VERSION 5.7 ;
  NOWIREEXTENSIONATPIN ON ;
  DIVIDERCHAR "/" ;
  BUSBITCHARS "[]" ;
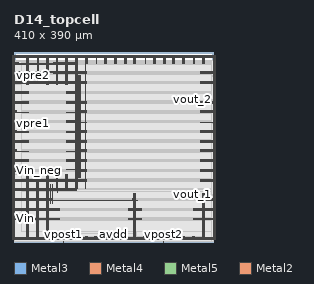
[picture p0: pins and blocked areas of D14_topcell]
MACRO D14_topcell
  CLASS BLOCK ;
  FOREIGN D14_topcell ;
  ORIGIN 0.000 0.000 ;
  SIZE 410.000 BY 390.000 ;
  PIN Vin
    DIRECTION INPUT ;
    USE SIGNAL ;
    ANTENNAGATEAREA 5.000000 ;
    PORT
      LAYER Metal3 ;
        RECT 0.000 48.160 0.560 48.720 ;
    END
  END Vin
  PIN Vin_neg
    DIRECTION INPUT ;
    USE SIGNAL ;
    ANTENNAGATEAREA 5.000000 ;
    PORT
      LAYER Metal3 ;
        RECT 0.000 145.600 0.560 146.160 ;
    END
  END Vin_neg
  PIN avdd
    DIRECTION INOUT ;
    USE POWER ;
    PORT
      LAYER Metal4 ;
        RECT -0.780 8.180 0.720 379.900 ;
    END
    PORT
      LAYER Metal4 ;
        RECT 409.200 8.180 410.700 379.900 ;
    END
    PORT
      LAYER Metal5 ;
        RECT -0.780 8.180 410.700 9.680 ;
    END
    PORT
      LAYER Metal5 ;
        RECT -0.780 378.400 410.700 379.900 ;
    END
    PORT
      LAYER Metal4 ;
        RECT 26.220 5.180 27.220 138.130 ;
    END
    PORT
      LAYER Metal4 ;
        RECT 26.220 323.710 27.220 382.900 ;
    END
    PORT
      LAYER Metal4 ;
        RECT 46.220 5.180 47.220 130.620 ;
    END
    PORT
      LAYER Metal4 ;
        RECT 46.220 378.400 47.220 382.900 ;
    END
    PORT
      LAYER Metal4 ;
        RECT 66.220 5.180 67.220 138.130 ;
    END
    PORT
      LAYER Metal4 ;
        RECT 66.220 323.710 67.220 382.900 ;
    END
    PORT
      LAYER Metal4 ;
        RECT 86.220 5.180 87.220 13.620 ;
    END
    PORT
      LAYER Metal4 ;
        RECT 86.220 104.780 87.220 138.130 ;
    END
    PORT
      LAYER Metal4 ;
        RECT 86.220 323.710 87.220 382.900 ;
    END
    PORT
      LAYER Metal4 ;
        RECT 106.220 5.180 107.220 10.930 ;
    END
    PORT
      LAYER Metal4 ;
        RECT 106.220 109.150 107.220 138.130 ;
    END
    PORT
      LAYER Metal4 ;
        RECT 106.220 323.710 107.220 382.900 ;
    END
    PORT
      LAYER Metal4 ;
        RECT 126.220 5.180 127.220 10.930 ;
    END
    PORT
      LAYER Metal4 ;
        RECT 126.220 109.150 127.220 382.900 ;
    END
    PORT
      LAYER Metal4 ;
        RECT 146.220 5.180 147.220 10.930 ;
    END
    PORT
      LAYER Metal4 ;
        RECT 146.220 109.150 147.220 382.900 ;
    END
    PORT
      LAYER Metal4 ;
        RECT 166.220 5.180 167.220 10.930 ;
    END
    PORT
      LAYER Metal4 ;
        RECT 166.220 379.020 167.220 382.900 ;
    END
    PORT
      LAYER Metal4 ;
        RECT 186.220 5.180 187.220 10.930 ;
    END
    PORT
      LAYER Metal4 ;
        RECT 186.220 365.385 187.220 382.900 ;
    END
    PORT
      LAYER Metal4 ;
        RECT 206.220 5.180 207.220 10.930 ;
    END
    PORT
      LAYER Metal4 ;
        RECT 206.220 365.385 207.220 382.900 ;
    END
    PORT
      LAYER Metal4 ;
        RECT 226.220 5.180 227.220 10.930 ;
    END
    PORT
      LAYER Metal4 ;
        RECT 226.220 365.385 227.220 382.900 ;
    END
    PORT
      LAYER Metal4 ;
        RECT 246.220 5.180 247.220 99.810 ;
    END
    PORT
      LAYER Metal4 ;
        RECT 246.220 365.385 247.220 382.900 ;
    END
    PORT
      LAYER Metal4 ;
        RECT 266.220 5.180 267.220 10.980 ;
    END
    PORT
      LAYER Metal4 ;
        RECT 266.220 379.020 267.220 382.900 ;
    END
    PORT
      LAYER Metal4 ;
        RECT 286.220 5.180 287.220 10.700 ;
    END
    PORT
      LAYER Metal4 ;
        RECT 286.220 365.385 287.220 382.900 ;
    END
    PORT
      LAYER Metal4 ;
        RECT 306.220 5.180 307.220 10.980 ;
    END
    PORT
      LAYER Metal4 ;
        RECT 306.220 365.385 307.220 382.900 ;
    END
    PORT
      LAYER Metal4 ;
        RECT 326.220 5.180 327.220 10.700 ;
    END
    PORT
      LAYER Metal4 ;
        RECT 326.220 365.385 327.220 382.900 ;
    END
    PORT
      LAYER Metal4 ;
        RECT 346.220 5.180 347.220 10.700 ;
    END
    PORT
      LAYER Metal4 ;
        RECT 346.220 365.385 347.220 382.900 ;
    END
    PORT
      LAYER Metal4 ;
        RECT 366.220 5.180 367.220 10.980 ;
    END
    PORT
      LAYER Metal4 ;
        RECT 366.220 379.020 367.220 382.900 ;
    END
    PORT
      LAYER Metal4 ;
        RECT 386.220 5.180 387.220 99.810 ;
    END
    PORT
      LAYER Metal4 ;
        RECT 386.220 365.385 387.220 382.900 ;
    END
    PORT
      LAYER Metal5 ;
        RECT -3.780 45.180 93.540 46.180 ;
    END
    PORT
      LAYER Metal5 ;
        RECT -3.780 65.180 93.540 66.180 ;
    END
    PORT
      LAYER Metal5 ;
        RECT -3.780 85.180 252.780 86.180 ;
    END
    PORT
      LAYER Metal5 ;
        RECT -3.780 105.180 128.700 106.180 ;
    END
    PORT
      LAYER Metal5 ;
        RECT -3.780 125.180 149.540 126.180 ;
    END
    PORT
      LAYER Metal5 ;
        RECT -3.780 145.180 8.300 146.180 ;
    END
    PORT
      LAYER Metal5 ;
        RECT -3.780 165.180 29.540 166.180 ;
    END
    PORT
      LAYER Metal5 ;
        RECT -3.780 185.180 29.540 186.180 ;
    END
    PORT
      LAYER Metal5 ;
        RECT -3.780 205.180 29.540 206.180 ;
    END
    PORT
      LAYER Metal5 ;
        RECT -3.780 225.180 29.540 226.180 ;
    END
    PORT
      LAYER Metal5 ;
        RECT -3.780 245.180 29.540 246.180 ;
    END
    PORT
      LAYER Metal5 ;
        RECT -3.780 265.180 29.540 266.180 ;
    END
    PORT
      LAYER Metal5 ;
        RECT -3.780 285.180 29.540 286.180 ;
    END
    PORT
      LAYER Metal5 ;
        RECT -3.780 305.180 29.540 306.180 ;
    END
    PORT
      LAYER Metal5 ;
        RECT -3.780 325.180 149.540 326.180 ;
    END
    PORT
      LAYER Metal5 ;
        RECT -3.780 345.180 9.080 346.180 ;
    END
    PORT
      LAYER Metal5 ;
        RECT -3.780 365.180 128.700 366.180 ;
    END
    PORT
      LAYER Metal5 ;
        RECT 81.920 345.180 149.540 346.180 ;
    END
    PORT
      LAYER Metal5 ;
        RECT 108.320 165.180 149.540 166.180 ;
    END
    PORT
      LAYER Metal5 ;
        RECT 108.320 185.180 149.540 186.180 ;
    END
    PORT
      LAYER Metal5 ;
        RECT 108.320 205.180 149.540 206.180 ;
    END
    PORT
      LAYER Metal5 ;
        RECT 108.320 225.180 149.540 226.180 ;
    END
    PORT
      LAYER Metal5 ;
        RECT 108.320 245.180 149.540 246.180 ;
    END
    PORT
      LAYER Metal5 ;
        RECT 108.320 265.180 149.540 266.180 ;
    END
    PORT
      LAYER Metal5 ;
        RECT 108.320 285.180 149.540 286.180 ;
    END
    PORT
      LAYER Metal5 ;
        RECT 108.320 305.180 128.700 306.180 ;
    END
    PORT
      LAYER Metal5 ;
        RECT 131.380 145.180 149.540 146.180 ;
    END
    PORT
      LAYER Metal5 ;
        RECT 234.320 45.180 262.540 46.180 ;
    END
    PORT
      LAYER Metal5 ;
        RECT 234.320 65.180 262.540 66.180 ;
    END
    PORT
      LAYER Metal5 ;
        RECT 368.565 45.180 413.700 46.180 ;
    END
    PORT
      LAYER Metal5 ;
        RECT 368.565 65.180 413.700 66.180 ;
    END
    PORT
      LAYER Metal5 ;
        RECT 382.440 125.180 413.700 126.180 ;
    END
    PORT
      LAYER Metal5 ;
        RECT 382.440 145.180 413.700 146.180 ;
    END
    PORT
      LAYER Metal5 ;
        RECT 382.440 165.180 413.700 166.180 ;
    END
    PORT
      LAYER Metal5 ;
        RECT 382.440 185.180 413.700 186.180 ;
    END
    PORT
      LAYER Metal5 ;
        RECT 382.440 205.180 413.700 206.180 ;
    END
    PORT
      LAYER Metal5 ;
        RECT 382.440 225.180 413.700 226.180 ;
    END
    PORT
      LAYER Metal5 ;
        RECT 382.440 245.180 413.700 246.180 ;
    END
    PORT
      LAYER Metal5 ;
        RECT 382.440 265.180 413.700 266.180 ;
    END
    PORT
      LAYER Metal5 ;
        RECT 382.440 285.180 413.700 286.180 ;
    END
    PORT
      LAYER Metal5 ;
        RECT 382.440 325.180 413.700 326.180 ;
    END
    PORT
      LAYER Metal5 ;
        RECT 382.440 345.180 413.700 346.180 ;
    END
    PORT
      LAYER Metal5 ;
        RECT 383.145 85.180 413.700 86.180 ;
    END
    PORT
      LAYER Metal4 ;
        RECT 74.820 78.100 75.820 117.900 ;
    END
    PORT
      LAYER Metal4 ;
        RECT 133.060 132.980 134.060 341.340 ;
    END
  END avdd
  PIN avss
    DIRECTION INOUT ;
    USE GROUND ;
    PORT
      LAYER Metal4 ;
        RECT -3.780 5.180 -2.280 382.900 ;
    END
    PORT
      LAYER Metal4 ;
        RECT 412.200 5.180 413.700 382.900 ;
    END
    PORT
      LAYER Metal5 ;
        RECT -3.780 5.180 413.700 6.680 ;
    END
    PORT
      LAYER Metal5 ;
        RECT -3.780 381.400 413.700 382.900 ;
    END
    PORT
      LAYER Metal4 ;
        RECT 29.220 5.180 30.220 138.130 ;
    END
    PORT
      LAYER Metal4 ;
        RECT 29.220 323.710 30.220 382.900 ;
    END
    PORT
      LAYER Metal4 ;
        RECT 49.220 5.180 50.220 130.620 ;
    END
    PORT
      LAYER Metal4 ;
        RECT 49.220 329.540 50.220 382.900 ;
    END
    PORT
      LAYER Metal4 ;
        RECT 69.220 5.180 70.220 138.130 ;
    END
    PORT
      LAYER Metal4 ;
        RECT 69.220 323.710 70.220 382.900 ;
    END
    PORT
      LAYER Metal4 ;
        RECT 89.220 5.180 90.220 17.120 ;
    END
    PORT
      LAYER Metal4 ;
        RECT 89.220 101.280 90.220 138.130 ;
    END
    PORT
      LAYER Metal4 ;
        RECT 89.220 323.710 90.220 382.900 ;
    END
    PORT
      LAYER Metal4 ;
        RECT 109.220 5.180 110.220 10.930 ;
    END
    PORT
      LAYER Metal4 ;
        RECT 109.220 109.150 110.220 138.130 ;
    END
    PORT
      LAYER Metal4 ;
        RECT 109.220 323.710 110.220 382.900 ;
    END
    PORT
      LAYER Metal4 ;
        RECT 129.220 5.180 130.220 10.930 ;
    END
    PORT
      LAYER Metal4 ;
        RECT 129.220 109.150 130.220 382.900 ;
    END
    PORT
      LAYER Metal4 ;
        RECT 149.220 5.180 150.220 10.930 ;
    END
    PORT
      LAYER Metal4 ;
        RECT 149.220 365.385 150.220 382.900 ;
    END
    PORT
      LAYER Metal4 ;
        RECT 169.220 5.180 170.220 10.930 ;
    END
    PORT
      LAYER Metal4 ;
        RECT 169.220 365.385 170.220 382.900 ;
    END
    PORT
      LAYER Metal4 ;
        RECT 189.220 5.180 190.220 10.930 ;
    END
    PORT
      LAYER Metal4 ;
        RECT 189.220 365.385 190.220 382.900 ;
    END
    PORT
      LAYER Metal4 ;
        RECT 209.220 5.180 210.220 10.930 ;
    END
    PORT
      LAYER Metal4 ;
        RECT 209.220 365.385 210.220 382.900 ;
    END
    PORT
      LAYER Metal4 ;
        RECT 229.220 5.180 230.220 10.930 ;
    END
    PORT
      LAYER Metal4 ;
        RECT 229.220 365.385 230.220 382.900 ;
    END
    PORT
      LAYER Metal4 ;
        RECT 249.220 5.180 250.220 99.810 ;
    END
    PORT
      LAYER Metal4 ;
        RECT 249.220 365.385 250.220 382.900 ;
    END
    PORT
      LAYER Metal4 ;
        RECT 269.220 5.180 270.220 10.980 ;
    END
    PORT
      LAYER Metal4 ;
        RECT 269.220 365.385 270.220 382.900 ;
    END
    PORT
      LAYER Metal4 ;
        RECT 289.220 5.180 290.220 10.700 ;
    END
    PORT
      LAYER Metal4 ;
        RECT 289.220 365.385 290.220 382.900 ;
    END
    PORT
      LAYER Metal4 ;
        RECT 309.220 5.180 310.220 10.980 ;
    END
    PORT
      LAYER Metal4 ;
        RECT 309.220 365.385 310.220 382.900 ;
    END
    PORT
      LAYER Metal4 ;
        RECT 329.220 5.180 330.220 10.700 ;
    END
    PORT
      LAYER Metal4 ;
        RECT 329.220 365.385 330.220 382.900 ;
    END
    PORT
      LAYER Metal4 ;
        RECT 349.220 5.180 350.220 10.980 ;
    END
    PORT
      LAYER Metal4 ;
        RECT 349.220 365.385 350.220 382.900 ;
    END
    PORT
      LAYER Metal4 ;
        RECT 369.220 5.180 370.220 10.980 ;
    END
    PORT
      LAYER Metal4 ;
        RECT 369.220 365.385 370.220 382.900 ;
    END
    PORT
      LAYER Metal4 ;
        RECT 389.220 5.180 390.220 99.810 ;
    END
    PORT
      LAYER Metal4 ;
        RECT 389.220 365.385 390.220 382.900 ;
    END
    PORT
      LAYER Metal5 ;
        RECT -3.780 48.180 93.540 49.180 ;
    END
    PORT
      LAYER Metal5 ;
        RECT -3.780 68.180 93.540 69.180 ;
    END
    PORT
      LAYER Metal5 ;
        RECT -3.780 88.180 78.800 89.180 ;
    END
    PORT
      LAYER Metal5 ;
        RECT -3.780 108.180 128.700 109.180 ;
    END
    PORT
      LAYER Metal5 ;
        RECT -3.780 128.180 149.540 129.180 ;
    END
    PORT
      LAYER Metal5 ;
        RECT -3.780 148.180 29.540 149.180 ;
    END
    PORT
      LAYER Metal5 ;
        RECT -3.780 168.180 29.540 169.180 ;
    END
    PORT
      LAYER Metal5 ;
        RECT -3.780 188.180 5.300 189.180 ;
    END
    PORT
      LAYER Metal5 ;
        RECT -3.780 208.180 29.540 209.180 ;
    END
    PORT
      LAYER Metal5 ;
        RECT -3.780 228.180 5.300 229.180 ;
    END
    PORT
      LAYER Metal5 ;
        RECT -3.780 248.180 29.540 249.180 ;
    END
    PORT
      LAYER Metal5 ;
        RECT -3.780 268.180 5.300 269.180 ;
    END
    PORT
      LAYER Metal5 ;
        RECT -3.780 288.180 29.540 289.180 ;
    END
    PORT
      LAYER Metal5 ;
        RECT -3.780 308.180 29.540 309.180 ;
    END
    PORT
      LAYER Metal5 ;
        RECT -3.780 328.180 149.540 329.180 ;
    END
    PORT
      LAYER Metal5 ;
        RECT -3.780 348.180 149.540 349.180 ;
    END
    PORT
      LAYER Metal5 ;
        RECT -3.780 368.180 9.080 369.180 ;
    END
    PORT
      LAYER Metal5 ;
        RECT 81.920 368.180 128.700 369.180 ;
    END
    PORT
      LAYER Metal5 ;
        RECT 108.320 148.180 149.540 149.180 ;
    END
    PORT
      LAYER Metal5 ;
        RECT 108.320 168.180 149.540 169.180 ;
    END
    PORT
      LAYER Metal5 ;
        RECT 108.320 208.180 149.540 209.180 ;
    END
    PORT
      LAYER Metal5 ;
        RECT 108.320 248.180 128.700 249.180 ;
    END
    PORT
      LAYER Metal5 ;
        RECT 108.320 288.180 149.540 289.180 ;
    END
    PORT
      LAYER Metal5 ;
        RECT 108.320 308.180 128.700 309.180 ;
    END
    PORT
      LAYER Metal5 ;
        RECT 134.380 188.180 149.540 189.180 ;
    END
    PORT
      LAYER Metal5 ;
        RECT 134.380 228.180 149.540 229.180 ;
    END
    PORT
      LAYER Metal5 ;
        RECT 134.380 268.180 149.540 269.180 ;
    END
    PORT
      LAYER Metal5 ;
        RECT 234.320 48.180 262.540 49.180 ;
    END
    PORT
      LAYER Metal5 ;
        RECT 234.320 68.180 262.540 69.180 ;
    END
    PORT
      LAYER Metal5 ;
        RECT 243.200 88.180 250.220 89.180 ;
    END
    PORT
      LAYER Metal5 ;
        RECT 368.565 48.180 413.700 49.180 ;
    END
    PORT
      LAYER Metal5 ;
        RECT 368.565 68.180 413.700 69.180 ;
    END
    PORT
      LAYER Metal5 ;
        RECT 382.440 128.180 413.700 129.180 ;
    END
    PORT
      LAYER Metal5 ;
        RECT 382.440 148.180 413.700 149.180 ;
    END
    PORT
      LAYER Metal5 ;
        RECT 382.440 168.180 413.700 169.180 ;
    END
    PORT
      LAYER Metal5 ;
        RECT 382.440 188.180 413.700 189.180 ;
    END
    PORT
      LAYER Metal5 ;
        RECT 382.440 208.180 413.700 209.180 ;
    END
    PORT
      LAYER Metal5 ;
        RECT 382.440 228.180 413.700 229.180 ;
    END
    PORT
      LAYER Metal5 ;
        RECT 382.440 268.180 413.700 269.180 ;
    END
    PORT
      LAYER Metal5 ;
        RECT 382.440 288.180 413.700 289.180 ;
    END
    PORT
      LAYER Metal5 ;
        RECT 382.440 328.180 413.700 329.180 ;
    END
    PORT
      LAYER Metal5 ;
        RECT 382.440 348.180 413.700 349.180 ;
    END
    PORT
      LAYER Metal5 ;
        RECT 386.145 88.180 413.700 89.180 ;
    END
    PORT
      LAYER Metal4 ;
        RECT 78.180 78.100 79.180 117.900 ;
    END
    PORT
      LAYER Metal4 ;
        RECT 136.420 132.980 137.420 341.340 ;
    END
  END avss
  PIN vout_1
    DIRECTION OUTPUT ;
    USE SIGNAL ;
    ANTENNAGATEAREA 5.000000 ;
    ANTENNADIFFAREA 10.568000 ;
    PORT
      LAYER Metal3 ;
        RECT 409.440 96.320 410.000 96.880 ;
    END
  END vout_1
  PIN vout_2
    DIRECTION OUTPUT ;
    USE SIGNAL ;
    ANTENNAGATEAREA 5.000000 ;
    ANTENNADIFFAREA 10.568000 ;
    PORT
      LAYER Metal3 ;
        RECT 409.440 291.200 410.000 291.760 ;
    END
  END vout_2
  PIN vpost1
    DIRECTION OUTPUT ;
    USE SIGNAL ;
    ANTENNAGATEAREA 1.260000 ;
    ANTENNADIFFAREA 0.750000 ;
    PORT
      LAYER Metal2 ;
        RECT 101.920 0.000 102.480 0.560 ;
    END
  END vpost1
  PIN vpost2
    DIRECTION OUTPUT ;
    USE SIGNAL ;
    ANTENNAGATEAREA 1.260000 ;
    ANTENNADIFFAREA 0.750000 ;
    PORT
      LAYER Metal2 ;
        RECT 306.880 0.000 307.440 0.560 ;
    END
  END vpost2
  PIN vpre1
    DIRECTION OUTPUT ;
    USE SIGNAL ;
    ANTENNADIFFAREA 0.750000 ;
    PORT
      LAYER Metal3 ;
        RECT 0.000 243.040 0.560 243.600 ;
    END
  END vpre1
  PIN vpre2
    DIRECTION OUTPUT ;
    USE SIGNAL ;
    ANTENNADIFFAREA 0.750000 ;
    PORT
      LAYER Metal3 ;
        RECT 0.000 340.480 0.560 341.040 ;
    END
  END vpre2
  OBS
      LAYER Nwell ;
        RECT 22.000 38.300 364.810 364.235 ;
      LAYER Metal1 ;
        RECT 6.720 15.380 403.200 372.700 ;
      LAYER Metal2 ;
        RECT 20.900 15.490 390.120 372.590 ;
      LAYER Metal3 ;
        RECT 0.560 341.340 409.440 372.540 ;
        RECT 0.860 340.180 409.440 341.340 ;
        RECT 0.560 292.060 409.440 340.180 ;
        RECT 0.560 290.900 409.140 292.060 ;
        RECT 0.560 243.900 409.440 290.900 ;
        RECT 0.860 242.740 409.440 243.900 ;
        RECT 0.560 146.460 409.440 242.740 ;
        RECT 0.860 145.300 409.440 146.460 ;
        RECT 0.560 97.180 409.440 145.300 ;
        RECT 0.560 96.020 409.140 97.180 ;
        RECT 0.560 49.020 409.440 96.020 ;
        RECT 0.860 47.860 409.440 49.020 ;
        RECT 0.560 0.140 409.440 47.860 ;
      LAYER Metal4 ;
        RECT 1.260 323.410 25.920 369.510 ;
        RECT 27.520 323.410 28.920 369.510 ;
        RECT 30.520 329.240 48.920 369.510 ;
        RECT 50.520 329.240 65.920 369.510 ;
        RECT 30.520 323.410 65.920 329.240 ;
        RECT 67.520 323.410 68.920 369.510 ;
        RECT 70.520 323.410 85.920 369.510 ;
        RECT 87.520 323.410 88.920 369.510 ;
        RECT 90.520 323.410 105.920 369.510 ;
        RECT 107.520 323.410 108.920 369.510 ;
        RECT 110.520 323.410 125.920 369.510 ;
        RECT 1.260 138.430 125.920 323.410 ;
        RECT 1.260 4.880 25.920 138.430 ;
        RECT 27.520 4.880 28.920 138.430 ;
        RECT 30.520 130.920 65.920 138.430 ;
        RECT 30.520 4.880 45.920 130.920 ;
        RECT 47.520 4.880 48.920 130.920 ;
        RECT 50.520 4.880 65.920 130.920 ;
        RECT 67.520 4.880 68.920 138.430 ;
        RECT 70.520 118.200 85.920 138.430 ;
        RECT 70.520 77.800 74.520 118.200 ;
        RECT 76.120 77.800 77.880 118.200 ;
        RECT 79.480 104.480 85.920 118.200 ;
        RECT 87.520 104.480 88.920 138.430 ;
        RECT 79.480 100.980 88.920 104.480 ;
        RECT 90.520 108.850 105.920 138.430 ;
        RECT 107.520 108.850 108.920 138.430 ;
        RECT 110.520 108.850 125.920 138.430 ;
        RECT 127.520 108.850 128.920 369.510 ;
        RECT 130.520 341.640 145.920 369.510 ;
        RECT 130.520 132.680 132.760 341.640 ;
        RECT 134.360 132.680 136.120 341.640 ;
        RECT 137.720 132.680 145.920 341.640 ;
        RECT 130.520 108.850 145.920 132.680 ;
        RECT 147.520 365.085 148.920 369.510 ;
        RECT 150.520 365.085 168.920 369.510 ;
        RECT 170.520 365.085 185.920 369.510 ;
        RECT 187.520 365.085 188.920 369.510 ;
        RECT 190.520 365.085 205.920 369.510 ;
        RECT 207.520 365.085 208.920 369.510 ;
        RECT 210.520 365.085 225.920 369.510 ;
        RECT 227.520 365.085 228.920 369.510 ;
        RECT 230.520 365.085 245.920 369.510 ;
        RECT 247.520 365.085 248.920 369.510 ;
        RECT 250.520 365.085 268.920 369.510 ;
        RECT 270.520 365.085 285.920 369.510 ;
        RECT 287.520 365.085 288.920 369.510 ;
        RECT 290.520 365.085 305.920 369.510 ;
        RECT 307.520 365.085 308.920 369.510 ;
        RECT 310.520 365.085 325.920 369.510 ;
        RECT 327.520 365.085 328.920 369.510 ;
        RECT 330.520 365.085 345.920 369.510 ;
        RECT 347.520 365.085 348.920 369.510 ;
        RECT 350.520 365.085 368.920 369.510 ;
        RECT 370.520 365.085 385.920 369.510 ;
        RECT 387.520 365.085 388.920 369.510 ;
        RECT 390.520 365.085 405.100 369.510 ;
        RECT 147.520 108.850 405.100 365.085 ;
        RECT 90.520 100.980 405.100 108.850 ;
        RECT 79.480 100.110 405.100 100.980 ;
        RECT 79.480 77.800 245.920 100.110 ;
        RECT 70.520 17.420 245.920 77.800 ;
        RECT 70.520 13.920 88.920 17.420 ;
        RECT 70.520 4.880 85.920 13.920 ;
        RECT 87.520 4.880 88.920 13.920 ;
        RECT 90.520 11.230 245.920 17.420 ;
        RECT 90.520 4.880 105.920 11.230 ;
        RECT 107.520 4.880 108.920 11.230 ;
        RECT 110.520 4.880 125.920 11.230 ;
        RECT 127.520 4.880 128.920 11.230 ;
        RECT 130.520 4.880 145.920 11.230 ;
        RECT 147.520 4.880 148.920 11.230 ;
        RECT 150.520 4.880 165.920 11.230 ;
        RECT 167.520 4.880 168.920 11.230 ;
        RECT 170.520 4.880 185.920 11.230 ;
        RECT 187.520 4.880 188.920 11.230 ;
        RECT 190.520 4.880 205.920 11.230 ;
        RECT 207.520 4.880 208.920 11.230 ;
        RECT 210.520 4.880 225.920 11.230 ;
        RECT 227.520 4.880 228.920 11.230 ;
        RECT 230.520 4.880 245.920 11.230 ;
        RECT 247.520 4.880 248.920 100.110 ;
        RECT 250.520 11.280 385.920 100.110 ;
        RECT 250.520 4.880 265.920 11.280 ;
        RECT 267.520 4.880 268.920 11.280 ;
        RECT 270.520 11.000 305.920 11.280 ;
        RECT 270.520 4.880 285.920 11.000 ;
        RECT 287.520 4.880 288.920 11.000 ;
        RECT 290.520 4.880 305.920 11.000 ;
        RECT 307.520 4.880 308.920 11.280 ;
        RECT 310.520 11.000 348.920 11.280 ;
        RECT 310.520 4.880 325.920 11.000 ;
        RECT 327.520 4.880 328.920 11.000 ;
        RECT 330.520 4.880 345.920 11.000 ;
        RECT 347.520 4.880 348.920 11.000 ;
        RECT 350.520 4.880 365.920 11.280 ;
        RECT 367.520 4.880 368.920 11.280 ;
        RECT 370.520 4.880 385.920 11.280 ;
        RECT 387.520 4.880 388.920 100.110 ;
        RECT 390.520 4.880 405.100 100.110 ;
        RECT 1.260 0.090 405.100 4.880 ;
      LAYER Metal5 ;
        RECT 16.220 367.580 81.320 368.460 ;
        RECT 129.300 367.580 405.100 368.460 ;
        RECT 16.220 366.780 405.100 367.580 ;
        RECT 129.300 364.580 405.100 366.780 ;
        RECT 16.220 349.780 405.100 364.580 ;
        RECT 150.140 347.580 381.840 349.780 ;
        RECT 16.220 346.780 405.100 347.580 ;
        RECT 16.220 344.580 81.320 346.780 ;
        RECT 150.140 344.580 381.840 346.780 ;
        RECT 16.220 329.780 405.100 344.580 ;
        RECT 150.140 327.580 381.840 329.780 ;
        RECT 16.220 326.780 405.100 327.580 ;
        RECT 150.140 324.580 381.840 326.780 ;
        RECT 16.220 309.780 405.100 324.580 ;
        RECT 30.140 307.580 107.720 309.780 ;
        RECT 129.300 307.580 405.100 309.780 ;
        RECT 16.220 306.780 405.100 307.580 ;
        RECT 30.140 304.580 107.720 306.780 ;
        RECT 129.300 304.580 405.100 306.780 ;
        RECT 16.220 289.780 405.100 304.580 ;
        RECT 30.140 287.580 107.720 289.780 ;
        RECT 150.140 287.580 381.840 289.780 ;
        RECT 16.220 286.780 405.100 287.580 ;
        RECT 30.140 284.580 107.720 286.780 ;
        RECT 150.140 284.580 381.840 286.780 ;
        RECT 16.220 269.780 405.100 284.580 ;
        RECT 16.220 267.580 133.780 269.780 ;
        RECT 150.140 267.580 381.840 269.780 ;
        RECT 16.220 266.780 405.100 267.580 ;
        RECT 30.140 264.580 107.720 266.780 ;
        RECT 150.140 264.580 381.840 266.780 ;
        RECT 16.220 249.780 405.100 264.580 ;
        RECT 30.140 247.580 107.720 249.780 ;
        RECT 129.300 247.580 405.100 249.780 ;
        RECT 16.220 246.780 405.100 247.580 ;
        RECT 30.140 244.580 107.720 246.780 ;
        RECT 150.140 244.580 381.840 246.780 ;
        RECT 16.220 229.780 405.100 244.580 ;
        RECT 16.220 227.580 133.780 229.780 ;
        RECT 150.140 227.580 381.840 229.780 ;
        RECT 16.220 226.780 405.100 227.580 ;
        RECT 30.140 224.580 107.720 226.780 ;
        RECT 150.140 224.580 381.840 226.780 ;
        RECT 16.220 209.780 405.100 224.580 ;
        RECT 30.140 207.580 107.720 209.780 ;
        RECT 150.140 207.580 381.840 209.780 ;
        RECT 16.220 206.780 405.100 207.580 ;
        RECT 30.140 204.580 107.720 206.780 ;
        RECT 150.140 204.580 381.840 206.780 ;
        RECT 16.220 189.780 405.100 204.580 ;
        RECT 16.220 187.580 133.780 189.780 ;
        RECT 150.140 187.580 381.840 189.780 ;
        RECT 16.220 186.780 405.100 187.580 ;
        RECT 30.140 184.580 107.720 186.780 ;
        RECT 150.140 184.580 381.840 186.780 ;
        RECT 16.220 169.780 405.100 184.580 ;
        RECT 30.140 167.580 107.720 169.780 ;
        RECT 150.140 167.580 381.840 169.780 ;
        RECT 16.220 166.780 405.100 167.580 ;
        RECT 30.140 164.580 107.720 166.780 ;
        RECT 150.140 164.580 381.840 166.780 ;
        RECT 16.220 149.780 405.100 164.580 ;
        RECT 30.140 147.580 107.720 149.780 ;
        RECT 150.140 147.580 381.840 149.780 ;
        RECT 16.220 146.780 405.100 147.580 ;
        RECT 16.220 144.580 130.780 146.780 ;
        RECT 150.140 144.580 381.840 146.780 ;
        RECT 16.220 129.780 405.100 144.580 ;
        RECT 150.140 127.580 381.840 129.780 ;
        RECT 16.220 126.780 405.100 127.580 ;
        RECT 150.140 124.580 381.840 126.780 ;
        RECT 16.220 109.780 405.100 124.580 ;
        RECT 129.300 107.580 405.100 109.780 ;
        RECT 16.220 106.780 405.100 107.580 ;
        RECT 129.300 104.580 405.100 106.780 ;
        RECT 16.220 89.780 405.100 104.580 ;
        RECT 79.400 87.580 242.600 89.780 ;
        RECT 250.820 87.580 385.545 89.780 ;
        RECT 16.220 86.780 405.100 87.580 ;
        RECT 253.380 84.580 382.545 86.780 ;
        RECT 16.220 69.780 405.100 84.580 ;
        RECT 94.140 67.580 233.720 69.780 ;
        RECT 263.140 67.580 367.965 69.780 ;
        RECT 16.220 66.780 405.100 67.580 ;
        RECT 94.140 64.580 233.720 66.780 ;
        RECT 263.140 64.580 367.965 66.780 ;
        RECT 16.220 49.780 405.100 64.580 ;
        RECT 94.140 47.580 233.720 49.780 ;
        RECT 263.140 47.580 367.965 49.780 ;
        RECT 16.220 46.780 405.100 47.580 ;
        RECT 94.140 44.580 233.720 46.780 ;
        RECT 263.140 44.580 367.965 46.780 ;
        RECT 16.220 21.260 405.100 44.580 ;
  END
END D14_topcell
END LIBRARY

